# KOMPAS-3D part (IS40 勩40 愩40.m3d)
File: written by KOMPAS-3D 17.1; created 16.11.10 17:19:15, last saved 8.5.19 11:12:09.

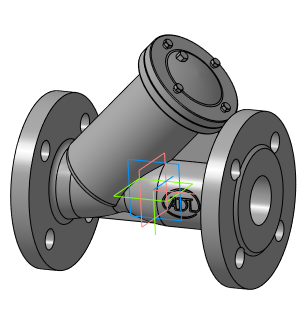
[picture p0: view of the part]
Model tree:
1. Плоскость XY
2. Плоскость ZX
3. Плоскость ZY
4. Ось X
5. Ось Y
6. Ось Z
7. Начало координат
8. Операция без истории:3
